VERSION 5.4 ;
NAMESCASESENSITIVE ON ;
BUSBITCHARS "[]" ;
DIVIDERCHAR "/" ;
UNITS
  DATABASE MICRONS 2000 ;
END UNITS
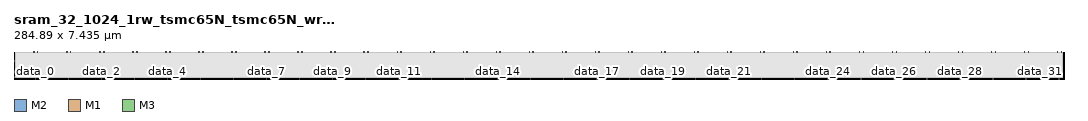
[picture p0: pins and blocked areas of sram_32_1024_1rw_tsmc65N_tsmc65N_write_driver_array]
MACRO sram_32_1024_1rw_tsmc65N_tsmc65N_write_driver_array
   CLASS BLOCK ;
   SIZE 284.89 BY 7.435 ;
   SYMMETRY X Y R90 ;
   PIN data_0
      DIRECTION INPUT ;
      PORT
         LAYER M2 ;
         RECT  5.715 0.0 5.815 0.1 ;
      END
   END data_0
   PIN data_1
      DIRECTION INPUT ;
      PORT
         LAYER M2 ;
         RECT  14.675 0.0 14.775 0.1 ;
      END
   END data_1
   PIN data_2
      DIRECTION INPUT ;
      PORT
         LAYER M2 ;
         RECT  23.635 0.0 23.735 0.1 ;
      END
   END data_2
   PIN data_3
      DIRECTION INPUT ;
      PORT
         LAYER M2 ;
         RECT  32.595 0.0 32.695 0.1 ;
      END
   END data_3
   PIN data_4
      DIRECTION INPUT ;
      PORT
         LAYER M2 ;
         RECT  41.555 0.0 41.655 0.1 ;
      END
   END data_4
   PIN data_5
      DIRECTION INPUT ;
      PORT
         LAYER M2 ;
         RECT  50.515 0.0 50.615 0.1 ;
      END
   END data_5
   PIN data_6
      DIRECTION INPUT ;
      PORT
         LAYER M2 ;
         RECT  59.475 0.0 59.575 0.1 ;
      END
   END data_6
   PIN data_7
      DIRECTION INPUT ;
      PORT
         LAYER M2 ;
         RECT  68.435 0.0 68.535 0.1 ;
      END
   END data_7
   PIN data_8
      DIRECTION INPUT ;
      PORT
         LAYER M2 ;
         RECT  77.395 0.0 77.495 0.1 ;
      END
   END data_8
   PIN data_9
      DIRECTION INPUT ;
      PORT
         LAYER M2 ;
         RECT  86.355 0.0 86.455 0.1 ;
      END
   END data_9
   PIN data_10
      DIRECTION INPUT ;
      PORT
         LAYER M2 ;
         RECT  95.315 0.0 95.415 0.1 ;
      END
   END data_10
   PIN data_11
      DIRECTION INPUT ;
      PORT
         LAYER M2 ;
         RECT  104.275 0.0 104.375 0.1 ;
      END
   END data_11
   PIN data_12
      DIRECTION INPUT ;
      PORT
         LAYER M2 ;
         RECT  113.235 0.0 113.335 0.1 ;
      END
   END data_12
   PIN data_13
      DIRECTION INPUT ;
      PORT
         LAYER M2 ;
         RECT  122.195 0.0 122.295 0.1 ;
      END
   END data_13
   PIN data_14
      DIRECTION INPUT ;
      PORT
         LAYER M2 ;
         RECT  131.155 0.0 131.255 0.1 ;
      END
   END data_14
   PIN data_15
      DIRECTION INPUT ;
      PORT
         LAYER M2 ;
         RECT  140.115 0.0 140.215 0.1 ;
      END
   END data_15
   PIN data_16
      DIRECTION INPUT ;
      PORT
         LAYER M2 ;
         RECT  149.075 0.0 149.175 0.1 ;
      END
   END data_16
   PIN data_17
      DIRECTION INPUT ;
      PORT
         LAYER M2 ;
         RECT  158.035 0.0 158.135 0.1 ;
      END
   END data_17
   PIN data_18
      DIRECTION INPUT ;
      PORT
         LAYER M2 ;
         RECT  166.995 0.0 167.095 0.1 ;
      END
   END data_18
   PIN data_19
      DIRECTION INPUT ;
      PORT
         LAYER M2 ;
         RECT  175.955 0.0 176.055 0.1 ;
      END
   END data_19
   PIN data_20
      DIRECTION INPUT ;
      PORT
         LAYER M2 ;
         RECT  184.915 0.0 185.015 0.1 ;
      END
   END data_20
   PIN data_21
      DIRECTION INPUT ;
      PORT
         LAYER M2 ;
         RECT  193.875 0.0 193.975 0.1 ;
      END
   END data_21
   PIN data_22
      DIRECTION INPUT ;
      PORT
         LAYER M2 ;
         RECT  202.835 0.0 202.935 0.1 ;
      END
   END data_22
   PIN data_23
      DIRECTION INPUT ;
      PORT
         LAYER M2 ;
         RECT  211.795 0.0 211.895 0.1 ;
      END
   END data_23
   PIN data_24
      DIRECTION INPUT ;
      PORT
         LAYER M2 ;
         RECT  220.755 0.0 220.855 0.1 ;
      END
   END data_24
   PIN data_25
      DIRECTION INPUT ;
      PORT
         LAYER M2 ;
         RECT  229.715 0.0 229.815 0.1 ;
      END
   END data_25
   PIN data_26
      DIRECTION INPUT ;
      PORT
         LAYER M2 ;
         RECT  238.675 0.0 238.775 0.1 ;
      END
   END data_26
   PIN data_27
      DIRECTION INPUT ;
      PORT
         LAYER M2 ;
         RECT  247.635 0.0 247.735 0.1 ;
      END
   END data_27
   PIN data_28
      DIRECTION INPUT ;
      PORT
         LAYER M2 ;
         RECT  256.595 0.0 256.695 0.1 ;
      END
   END data_28
   PIN data_29
      DIRECTION INPUT ;
      PORT
         LAYER M2 ;
         RECT  265.555 0.0 265.655 0.1 ;
      END
   END data_29
   PIN data_30
      DIRECTION INPUT ;
      PORT
         LAYER M2 ;
         RECT  274.515 0.0 274.615 0.1 ;
      END
   END data_30
   PIN data_31
      DIRECTION INPUT ;
      PORT
         LAYER M2 ;
         RECT  283.475 0.0 283.575 0.1 ;
      END
   END data_31
   PIN bl_0
      DIRECTION OUTPUT ;
      PORT
         LAYER M2 ;
         RECT  5.36 7.295 5.5 7.435 ;
      END
   END bl_0
   PIN br_0
      DIRECTION OUTPUT ;
      PORT
         LAYER M2 ;
         RECT  6.36 7.295 6.5 7.435 ;
      END
   END br_0
   PIN bl_1
      DIRECTION OUTPUT ;
      PORT
         LAYER M2 ;
         RECT  14.32 7.295 14.46 7.435 ;
      END
   END bl_1
   PIN br_1
      DIRECTION OUTPUT ;
      PORT
         LAYER M2 ;
         RECT  15.32 7.295 15.46 7.435 ;
      END
   END br_1
   PIN bl_2
      DIRECTION OUTPUT ;
      PORT
         LAYER M2 ;
         RECT  23.28 7.295 23.42 7.435 ;
      END
   END bl_2
   PIN br_2
      DIRECTION OUTPUT ;
      PORT
         LAYER M2 ;
         RECT  24.28 7.295 24.42 7.435 ;
      END
   END br_2
   PIN bl_3
      DIRECTION OUTPUT ;
      PORT
         LAYER M2 ;
         RECT  32.24 7.295 32.38 7.435 ;
      END
   END bl_3
   PIN br_3
      DIRECTION OUTPUT ;
      PORT
         LAYER M2 ;
         RECT  33.24 7.295 33.38 7.435 ;
      END
   END br_3
   PIN bl_4
      DIRECTION OUTPUT ;
      PORT
         LAYER M2 ;
         RECT  41.2 7.295 41.34 7.435 ;
      END
   END bl_4
   PIN br_4
      DIRECTION OUTPUT ;
      PORT
         LAYER M2 ;
         RECT  42.2 7.295 42.34 7.435 ;
      END
   END br_4
   PIN bl_5
      DIRECTION OUTPUT ;
      PORT
         LAYER M2 ;
         RECT  50.16 7.295 50.3 7.435 ;
      END
   END bl_5
   PIN br_5
      DIRECTION OUTPUT ;
      PORT
         LAYER M2 ;
         RECT  51.16 7.295 51.3 7.435 ;
      END
   END br_5
   PIN bl_6
      DIRECTION OUTPUT ;
      PORT
         LAYER M2 ;
         RECT  59.12 7.295 59.26 7.435 ;
      END
   END bl_6
   PIN br_6
      DIRECTION OUTPUT ;
      PORT
         LAYER M2 ;
         RECT  60.12 7.295 60.26 7.435 ;
      END
   END br_6
   PIN bl_7
      DIRECTION OUTPUT ;
      PORT
         LAYER M2 ;
         RECT  68.08 7.295 68.22 7.435 ;
      END
   END bl_7
   PIN br_7
      DIRECTION OUTPUT ;
      PORT
         LAYER M2 ;
         RECT  69.08 7.295 69.22 7.435 ;
      END
   END br_7
   PIN bl_8
      DIRECTION OUTPUT ;
      PORT
         LAYER M2 ;
         RECT  77.04 7.295 77.18 7.435 ;
      END
   END bl_8
   PIN br_8
      DIRECTION OUTPUT ;
      PORT
         LAYER M2 ;
         RECT  78.04 7.295 78.18 7.435 ;
      END
   END br_8
   PIN bl_9
      DIRECTION OUTPUT ;
      PORT
         LAYER M2 ;
         RECT  86.0 7.295 86.14 7.435 ;
      END
   END bl_9
   PIN br_9
      DIRECTION OUTPUT ;
      PORT
         LAYER M2 ;
         RECT  87.0 7.295 87.14 7.435 ;
      END
   END br_9
   PIN bl_10
      DIRECTION OUTPUT ;
      PORT
         LAYER M2 ;
         RECT  94.96 7.295 95.1 7.435 ;
      END
   END bl_10
   PIN br_10
      DIRECTION OUTPUT ;
      PORT
         LAYER M2 ;
         RECT  95.96 7.295 96.1 7.435 ;
      END
   END br_10
   PIN bl_11
      DIRECTION OUTPUT ;
      PORT
         LAYER M2 ;
         RECT  103.92 7.295 104.06 7.435 ;
      END
   END bl_11
   PIN br_11
      DIRECTION OUTPUT ;
      PORT
         LAYER M2 ;
         RECT  104.92 7.295 105.06 7.435 ;
      END
   END br_11
   PIN bl_12
      DIRECTION OUTPUT ;
      PORT
         LAYER M2 ;
         RECT  112.88 7.295 113.02 7.435 ;
      END
   END bl_12
   PIN br_12
      DIRECTION OUTPUT ;
      PORT
         LAYER M2 ;
         RECT  113.88 7.295 114.02 7.435 ;
      END
   END br_12
   PIN bl_13
      DIRECTION OUTPUT ;
      PORT
         LAYER M2 ;
         RECT  121.84 7.295 121.98 7.435 ;
      END
   END bl_13
   PIN br_13
      DIRECTION OUTPUT ;
      PORT
         LAYER M2 ;
         RECT  122.84 7.295 122.98 7.435 ;
      END
   END br_13
   PIN bl_14
      DIRECTION OUTPUT ;
      PORT
         LAYER M2 ;
         RECT  130.8 7.295 130.94 7.435 ;
      END
   END bl_14
   PIN br_14
      DIRECTION OUTPUT ;
      PORT
         LAYER M2 ;
         RECT  131.8 7.295 131.94 7.435 ;
      END
   END br_14
   PIN bl_15
      DIRECTION OUTPUT ;
      PORT
         LAYER M2 ;
         RECT  139.76 7.295 139.9 7.435 ;
      END
   END bl_15
   PIN br_15
      DIRECTION OUTPUT ;
      PORT
         LAYER M2 ;
         RECT  140.76 7.295 140.9 7.435 ;
      END
   END br_15
   PIN bl_16
      DIRECTION OUTPUT ;
      PORT
         LAYER M2 ;
         RECT  148.72 7.295 148.86 7.435 ;
      END
   END bl_16
   PIN br_16
      DIRECTION OUTPUT ;
      PORT
         LAYER M2 ;
         RECT  149.72 7.295 149.86 7.435 ;
      END
   END br_16
   PIN bl_17
      DIRECTION OUTPUT ;
      PORT
         LAYER M2 ;
         RECT  157.68 7.295 157.82 7.435 ;
      END
   END bl_17
   PIN br_17
      DIRECTION OUTPUT ;
      PORT
         LAYER M2 ;
         RECT  158.68 7.295 158.82 7.435 ;
      END
   END br_17
   PIN bl_18
      DIRECTION OUTPUT ;
      PORT
         LAYER M2 ;
         RECT  166.64 7.295 166.78 7.435 ;
      END
   END bl_18
   PIN br_18
      DIRECTION OUTPUT ;
      PORT
         LAYER M2 ;
         RECT  167.64 7.295 167.78 7.435 ;
      END
   END br_18
   PIN bl_19
      DIRECTION OUTPUT ;
      PORT
         LAYER M2 ;
         RECT  175.6 7.295 175.74 7.435 ;
      END
   END bl_19
   PIN br_19
      DIRECTION OUTPUT ;
      PORT
         LAYER M2 ;
         RECT  176.6 7.295 176.74 7.435 ;
      END
   END br_19
   PIN bl_20
      DIRECTION OUTPUT ;
      PORT
         LAYER M2 ;
         RECT  184.56 7.295 184.7 7.435 ;
      END
   END bl_20
   PIN br_20
      DIRECTION OUTPUT ;
      PORT
         LAYER M2 ;
         RECT  185.56 7.295 185.7 7.435 ;
      END
   END br_20
   PIN bl_21
      DIRECTION OUTPUT ;
      PORT
         LAYER M2 ;
         RECT  193.52 7.295 193.66 7.435 ;
      END
   END bl_21
   PIN br_21
      DIRECTION OUTPUT ;
      PORT
         LAYER M2 ;
         RECT  194.52 7.295 194.66 7.435 ;
      END
   END br_21
   PIN bl_22
      DIRECTION OUTPUT ;
      PORT
         LAYER M2 ;
         RECT  202.48 7.295 202.62 7.435 ;
      END
   END bl_22
   PIN br_22
      DIRECTION OUTPUT ;
      PORT
         LAYER M2 ;
         RECT  203.48 7.295 203.62 7.435 ;
      END
   END br_22
   PIN bl_23
      DIRECTION OUTPUT ;
      PORT
         LAYER M2 ;
         RECT  211.44 7.295 211.58 7.435 ;
      END
   END bl_23
   PIN br_23
      DIRECTION OUTPUT ;
      PORT
         LAYER M2 ;
         RECT  212.44 7.295 212.58 7.435 ;
      END
   END br_23
   PIN bl_24
      DIRECTION OUTPUT ;
      PORT
         LAYER M2 ;
         RECT  220.4 7.295 220.54 7.435 ;
      END
   END bl_24
   PIN br_24
      DIRECTION OUTPUT ;
      PORT
         LAYER M2 ;
         RECT  221.4 7.295 221.54 7.435 ;
      END
   END br_24
   PIN bl_25
      DIRECTION OUTPUT ;
      PORT
         LAYER M2 ;
         RECT  229.36 7.295 229.5 7.435 ;
      END
   END bl_25
   PIN br_25
      DIRECTION OUTPUT ;
      PORT
         LAYER M2 ;
         RECT  230.36 7.295 230.5 7.435 ;
      END
   END br_25
   PIN bl_26
      DIRECTION OUTPUT ;
      PORT
         LAYER M2 ;
         RECT  238.32 7.295 238.46 7.435 ;
      END
   END bl_26
   PIN br_26
      DIRECTION OUTPUT ;
      PORT
         LAYER M2 ;
         RECT  239.32 7.295 239.46 7.435 ;
      END
   END br_26
   PIN bl_27
      DIRECTION OUTPUT ;
      PORT
         LAYER M2 ;
         RECT  247.28 7.295 247.42 7.435 ;
      END
   END bl_27
   PIN br_27
      DIRECTION OUTPUT ;
      PORT
         LAYER M2 ;
         RECT  248.28 7.295 248.42 7.435 ;
      END
   END br_27
   PIN bl_28
      DIRECTION OUTPUT ;
      PORT
         LAYER M2 ;
         RECT  256.24 7.295 256.38 7.435 ;
      END
   END bl_28
   PIN br_28
      DIRECTION OUTPUT ;
      PORT
         LAYER M2 ;
         RECT  257.24 7.295 257.38 7.435 ;
      END
   END br_28
   PIN bl_29
      DIRECTION OUTPUT ;
      PORT
         LAYER M2 ;
         RECT  265.2 7.295 265.34 7.435 ;
      END
   END bl_29
   PIN br_29
      DIRECTION OUTPUT ;
      PORT
         LAYER M2 ;
         RECT  266.2 7.295 266.34 7.435 ;
      END
   END br_29
   PIN bl_30
      DIRECTION OUTPUT ;
      PORT
         LAYER M2 ;
         RECT  274.16 7.295 274.3 7.435 ;
      END
   END bl_30
   PIN br_30
      DIRECTION OUTPUT ;
      PORT
         LAYER M2 ;
         RECT  275.16 7.295 275.3 7.435 ;
      END
   END br_30
   PIN bl_31
      DIRECTION OUTPUT ;
      PORT
         LAYER M2 ;
         RECT  283.12 7.295 283.26 7.435 ;
      END
   END bl_31
   PIN br_31
      DIRECTION OUTPUT ;
      PORT
         LAYER M2 ;
         RECT  284.12 7.295 284.26 7.435 ;
      END
   END br_31
   PIN en
      DIRECTION INPUT ;
      PORT
         LAYER M1 ;
         RECT  0.0 0.43 0.14 0.57 ;
      END
   END en
   PIN vdd
      DIRECTION INOUT ;
      USE POWER ; 
      SHAPE ABUTMENT ; 
      PORT
         LAYER M3 ;
         RECT  0.0 4.855 0.14 4.995 ;
      END
   END vdd
   PIN gnd
      DIRECTION INOUT ;
      USE GROUND ; 
      SHAPE ABUTMENT ; 
      PORT
         LAYER M3 ;
         RECT  0.0 4.18 0.14 4.32 ;
      END
   END gnd
   OBS
   LAYER  M1 ;
      RECT  0.32 0.81 0.38 7.115 ;
      RECT  0.38 0.32 284.57 0.81 ;
      RECT  0.38 0.81 284.57 7.115 ;
   LAYER  M2 ;
      RECT  0.32 0.32 5.16 7.095 ;
      RECT  0.32 7.095 5.16 7.115 ;
      RECT  5.16 0.32 5.7 7.095 ;
      RECT  5.7 0.32 284.57 7.095 ;
      RECT  5.7 7.095 6.16 7.115 ;
      RECT  6.7 7.095 14.12 7.115 ;
      RECT  14.66 7.095 15.12 7.115 ;
      RECT  15.66 7.095 23.08 7.115 ;
      RECT  23.62 7.095 24.08 7.115 ;
      RECT  24.62 7.095 32.04 7.115 ;
      RECT  32.58 7.095 33.04 7.115 ;
      RECT  33.58 7.095 41.0 7.115 ;
      RECT  41.54 7.095 42.0 7.115 ;
      RECT  42.54 7.095 49.96 7.115 ;
      RECT  50.5 7.095 50.96 7.115 ;
      RECT  51.5 7.095 58.92 7.115 ;
      RECT  59.46 7.095 59.92 7.115 ;
      RECT  60.46 7.095 67.88 7.115 ;
      RECT  68.42 7.095 68.88 7.115 ;
      RECT  69.42 7.095 76.84 7.115 ;
      RECT  77.38 7.095 77.84 7.115 ;
      RECT  78.38 7.095 85.8 7.115 ;
      RECT  86.34 7.095 86.8 7.115 ;
      RECT  87.34 7.095 94.76 7.115 ;
      RECT  95.3 7.095 95.76 7.115 ;
      RECT  96.3 7.095 103.72 7.115 ;
      RECT  104.26 7.095 104.72 7.115 ;
      RECT  105.26 7.095 112.68 7.115 ;
      RECT  113.22 7.095 113.68 7.115 ;
      RECT  114.22 7.095 121.64 7.115 ;
      RECT  122.18 7.095 122.64 7.115 ;
      RECT  123.18 7.095 130.6 7.115 ;
      RECT  131.14 7.095 131.6 7.115 ;
      RECT  132.14 7.095 139.56 7.115 ;
      RECT  140.1 7.095 140.56 7.115 ;
      RECT  141.1 7.095 148.52 7.115 ;
      RECT  149.06 7.095 149.52 7.115 ;
      RECT  150.06 7.095 157.48 7.115 ;
      RECT  158.02 7.095 158.48 7.115 ;
      RECT  159.02 7.095 166.44 7.115 ;
      RECT  166.98 7.095 167.44 7.115 ;
      RECT  167.98 7.095 175.4 7.115 ;
      RECT  175.94 7.095 176.4 7.115 ;
      RECT  176.94 7.095 184.36 7.115 ;
      RECT  184.9 7.095 185.36 7.115 ;
      RECT  185.9 7.095 193.32 7.115 ;
      RECT  193.86 7.095 194.32 7.115 ;
      RECT  194.86 7.095 202.28 7.115 ;
      RECT  202.82 7.095 203.28 7.115 ;
      RECT  203.82 7.095 211.24 7.115 ;
      RECT  211.78 7.095 212.24 7.115 ;
      RECT  212.78 7.095 220.2 7.115 ;
      RECT  220.74 7.095 221.2 7.115 ;
      RECT  221.74 7.095 229.16 7.115 ;
      RECT  229.7 7.095 230.16 7.115 ;
      RECT  230.7 7.095 238.12 7.115 ;
      RECT  238.66 7.095 239.12 7.115 ;
      RECT  239.66 7.095 247.08 7.115 ;
      RECT  247.62 7.095 248.08 7.115 ;
      RECT  248.62 7.095 256.04 7.115 ;
      RECT  256.58 7.095 257.04 7.115 ;
      RECT  257.58 7.095 265.0 7.115 ;
      RECT  265.54 7.095 266.0 7.115 ;
      RECT  266.54 7.095 273.96 7.115 ;
      RECT  274.5 7.095 274.96 7.115 ;
      RECT  275.5 7.095 282.92 7.115 ;
      RECT  283.46 7.095 283.92 7.115 ;
      RECT  284.46 7.095 284.57 7.115 ;
   LAYER  M3 ;
      RECT  0.32 5.195 0.34 7.115 ;
      RECT  0.34 0.32 284.57 4.655 ;
      RECT  0.34 4.655 284.57 5.195 ;
      RECT  0.34 5.195 284.57 7.115 ;
      RECT  0.32 0.32 0.34 3.98 ;
      RECT  0.32 4.52 0.34 4.655 ;
   LAYER  M4 ;
      RECT  0.32 0.32 284.57 7.115 ;
   END
END    sram_32_1024_1rw_tsmc65N_tsmc65N_write_driver_array
END    LIBRARY
